VERSION 5.7 ;
  NOWIREEXTENSIONATPIN ON ;
  DIVIDERCHAR "/" ;
  BUSBITCHARS "[]" ;
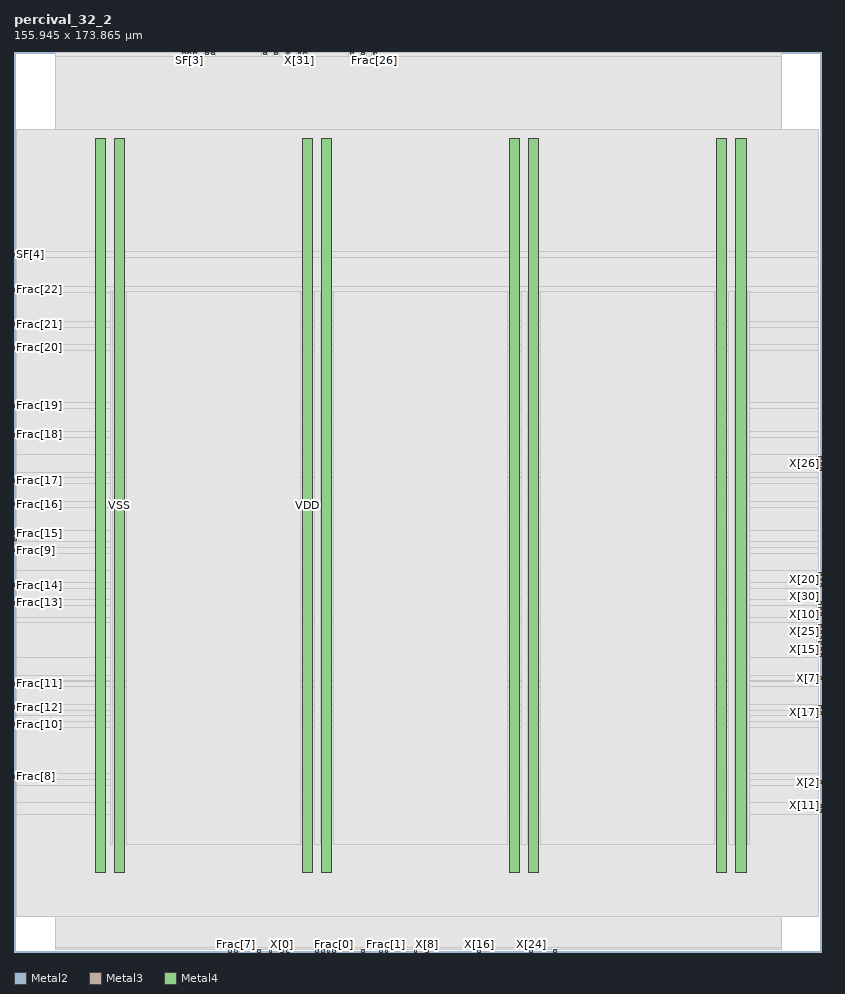
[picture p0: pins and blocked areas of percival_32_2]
MACRO percival_32_2
  CLASS BLOCK ;
  FOREIGN percival_32_2 ;
  ORIGIN 0.000 0.000 ;
  SIZE 155.945 BY 173.865 ;
  PIN Frac[0]
    DIRECTION OUTPUT ;
    USE SIGNAL ;
    ANTENNADIFFAREA 1.986000 ;
    PORT
      LAYER Metal2 ;
        RECT 61.600 0.000 62.160 0.560 ;
    END
  END Frac[0]
  PIN Frac[10]
    DIRECTION OUTPUT ;
    USE SIGNAL ;
    ANTENNADIFFAREA 1.986000 ;
    PORT
      LAYER Metal3 ;
        RECT 0.000 43.680 0.560 44.240 ;
    END
  END Frac[10]
  PIN Frac[11]
    DIRECTION OUTPUT ;
    USE SIGNAL ;
    ANTENNADIFFAREA 1.986000 ;
    PORT
      LAYER Metal3 ;
        RECT 0.000 51.520 0.560 52.080 ;
    END
  END Frac[11]
  PIN Frac[12]
    DIRECTION OUTPUT ;
    USE SIGNAL ;
    ANTENNADIFFAREA 1.986000 ;
    PORT
      LAYER Metal3 ;
        RECT 0.000 47.040 0.560 47.600 ;
    END
  END Frac[12]
  PIN Frac[13]
    DIRECTION OUTPUT ;
    USE SIGNAL ;
    ANTENNADIFFAREA 1.986000 ;
    PORT
      LAYER Metal3 ;
        RECT 0.000 67.200 0.560 67.760 ;
    END
  END Frac[13]
  PIN Frac[14]
    DIRECTION OUTPUT ;
    USE SIGNAL ;
    ANTENNADIFFAREA 1.986000 ;
    PORT
      LAYER Metal3 ;
        RECT 0.000 70.560 0.560 71.120 ;
    END
  END Frac[14]
  PIN Frac[15]
    DIRECTION OUTPUT ;
    USE SIGNAL ;
    ANTENNADIFFAREA 1.986000 ;
    PORT
      LAYER Metal3 ;
        RECT 0.000 80.640 0.560 81.200 ;
    END
  END Frac[15]
  PIN Frac[16]
    DIRECTION OUTPUT ;
    USE SIGNAL ;
    ANTENNADIFFAREA 1.986000 ;
    PORT
      LAYER Metal3 ;
        RECT 0.000 86.240 0.560 86.800 ;
    END
  END Frac[16]
  PIN Frac[17]
    DIRECTION OUTPUT ;
    USE SIGNAL ;
    ANTENNADIFFAREA 1.986000 ;
    PORT
      LAYER Metal3 ;
        RECT 0.000 90.720 0.560 91.280 ;
    END
  END Frac[17]
  PIN Frac[18]
    DIRECTION OUTPUT ;
    USE SIGNAL ;
    ANTENNADIFFAREA 1.986000 ;
    PORT
      LAYER Metal3 ;
        RECT 0.000 99.680 0.560 100.240 ;
    END
  END Frac[18]
  PIN Frac[19]
    DIRECTION OUTPUT ;
    USE SIGNAL ;
    ANTENNADIFFAREA 1.986000 ;
    PORT
      LAYER Metal3 ;
        RECT 0.000 105.280 0.560 105.840 ;
    END
  END Frac[19]
  PIN Frac[1]
    DIRECTION OUTPUT ;
    USE SIGNAL ;
    ANTENNADIFFAREA 1.986000 ;
    PORT
      LAYER Metal2 ;
        RECT 71.680 0.000 72.240 0.560 ;
    END
  END Frac[1]
  PIN Frac[20]
    DIRECTION OUTPUT ;
    USE SIGNAL ;
    ANTENNADIFFAREA 1.986000 ;
    PORT
      LAYER Metal3 ;
        RECT 0.000 116.480 0.560 117.040 ;
    END
  END Frac[20]
  PIN Frac[21]
    DIRECTION OUTPUT ;
    USE SIGNAL ;
    ANTENNADIFFAREA 1.986000 ;
    PORT
      LAYER Metal3 ;
        RECT 0.000 120.960 0.560 121.520 ;
    END
  END Frac[21]
  PIN Frac[22]
    DIRECTION OUTPUT ;
    USE SIGNAL ;
    ANTENNADIFFAREA 1.986000 ;
    PORT
      LAYER Metal3 ;
        RECT 0.000 127.680 0.560 128.240 ;
    END
  END Frac[22]
  PIN Frac[23]
    DIRECTION OUTPUT ;
    USE SIGNAL ;
    ANTENNADIFFAREA 1.986000 ;
    PORT
      LAYER Metal2 ;
        RECT 48.160 173.305 48.720 173.865 ;
    END
  END Frac[23]
  PIN Frac[24]
    DIRECTION OUTPUT ;
    USE SIGNAL ;
    ANTENNADIFFAREA 1.986000 ;
    PORT
      LAYER Metal2 ;
        RECT 50.400 173.305 50.960 173.865 ;
    END
  END Frac[24]
  PIN Frac[25]
    DIRECTION OUTPUT ;
    USE SIGNAL ;
    ANTENNADIFFAREA 1.986000 ;
    PORT
      LAYER Metal2 ;
        RECT 52.640 173.305 53.200 173.865 ;
    END
  END Frac[25]
  PIN Frac[26]
    DIRECTION OUTPUT ;
    USE SIGNAL ;
    ANTENNADIFFAREA 1.986000 ;
    PORT
      LAYER Metal2 ;
        RECT 69.440 173.305 70.000 173.865 ;
    END
  END Frac[26]
  PIN Frac[2]
    DIRECTION OUTPUT ;
    USE SIGNAL ;
    ANTENNADIFFAREA 1.986000 ;
    PORT
      LAYER Metal3 ;
        RECT 0.000 79.520 0.560 80.080 ;
    END
  END Frac[2]
  PIN Frac[3]
    DIRECTION OUTPUT ;
    USE SIGNAL ;
    ANTENNADIFFAREA 1.986000 ;
    PORT
      LAYER Metal2 ;
        RECT 77.280 0.000 77.840 0.560 ;
    END
  END Frac[3]
  PIN Frac[4]
    DIRECTION OUTPUT ;
    USE SIGNAL ;
    ANTENNADIFFAREA 1.986000 ;
    PORT
      LAYER Metal2 ;
        RECT 59.360 0.000 59.920 0.560 ;
    END
  END Frac[4]
  PIN Frac[5]
    DIRECTION OUTPUT ;
    USE SIGNAL ;
    ANTENNADIFFAREA 1.986000 ;
    PORT
      LAYER Metal2 ;
        RECT 47.040 0.000 47.600 0.560 ;
    END
  END Frac[5]
  PIN Frac[6]
    DIRECTION OUTPUT ;
    USE SIGNAL ;
    ANTENNADIFFAREA 1.986000 ;
    PORT
      LAYER Metal2 ;
        RECT 41.440 0.000 42.000 0.560 ;
    END
  END Frac[6]
  PIN Frac[7]
    DIRECTION OUTPUT ;
    USE SIGNAL ;
    ANTENNADIFFAREA 1.986000 ;
    PORT
      LAYER Metal2 ;
        RECT 42.560 0.000 43.120 0.560 ;
    END
  END Frac[7]
  PIN Frac[8]
    DIRECTION OUTPUT ;
    USE SIGNAL ;
    ANTENNADIFFAREA 1.986000 ;
    PORT
      LAYER Metal3 ;
        RECT 0.000 33.600 0.560 34.160 ;
    END
  END Frac[8]
  PIN Frac[9]
    DIRECTION OUTPUT ;
    USE SIGNAL ;
    ANTENNADIFFAREA 2.365600 ;
    PORT
      LAYER Metal3 ;
        RECT 0.000 77.280 0.560 77.840 ;
    END
  END Frac[9]
  PIN NZN
    DIRECTION OUTPUT ;
    USE SIGNAL ;
    ANTENNADIFFAREA 1.986000 ;
    PORT
      LAYER Metal2 ;
        RECT 104.160 0.000 104.720 0.560 ;
    END
  END NZN
  PIN SF[0]
    DIRECTION OUTPUT ;
    USE SIGNAL ;
    ANTENNADIFFAREA 1.986000 ;
    PORT
      LAYER Metal2 ;
        RECT 64.960 173.305 65.520 173.865 ;
    END
  END SF[0]
  PIN SF[1]
    DIRECTION OUTPUT ;
    USE SIGNAL ;
    ANTENNADIFFAREA 1.986000 ;
    PORT
      LAYER Metal2 ;
        RECT 67.200 173.305 67.760 173.865 ;
    END
  END SF[1]
  PIN SF[2]
    DIRECTION OUTPUT ;
    USE SIGNAL ;
    ANTENNADIFFAREA 1.986000 ;
    PORT
      LAYER Metal2 ;
        RECT 32.480 173.305 33.040 173.865 ;
    END
  END SF[2]
  PIN SF[3]
    DIRECTION OUTPUT ;
    USE SIGNAL ;
    ANTENNADIFFAREA 1.986000 ;
    PORT
      LAYER Metal2 ;
        RECT 33.600 173.305 34.160 173.865 ;
    END
  END SF[3]
  PIN SF[4]
    DIRECTION OUTPUT ;
    USE SIGNAL ;
    ANTENNADIFFAREA 1.986000 ;
    PORT
      LAYER Metal3 ;
        RECT 0.000 134.400 0.560 134.960 ;
    END
  END SF[4]
  PIN SF[5]
    DIRECTION OUTPUT ;
    USE SIGNAL ;
    ANTENNADIFFAREA 1.986000 ;
    PORT
      LAYER Metal2 ;
        RECT 38.080 173.305 38.640 173.865 ;
    END
  END SF[5]
  PIN SF[6]
    DIRECTION OUTPUT ;
    USE SIGNAL ;
    ANTENNADIFFAREA 1.986000 ;
    PORT
      LAYER Metal2 ;
        RECT 34.720 173.305 35.280 173.865 ;
    END
  END SF[6]
  PIN SF[7]
    DIRECTION OUTPUT ;
    USE SIGNAL ;
    ANTENNADIFFAREA 1.986000 ;
    PORT
      LAYER Metal2 ;
        RECT 36.960 173.305 37.520 173.865 ;
    END
  END SF[7]
  PIN Sign
    DIRECTION OUTPUT ;
    USE SIGNAL ;
    ANTENNADIFFAREA 1.986000 ;
    PORT
      LAYER Metal2 ;
        RECT 56.000 173.305 56.560 173.865 ;
    END
  END Sign
  PIN VDD
    DIRECTION INOUT ;
    USE POWER ;
    PORT
      LAYER Metal4 ;
        RECT 15.720 15.380 17.720 157.100 ;
    END
    PORT
      LAYER Metal4 ;
        RECT 55.720 15.380 57.720 157.100 ;
    END
    PORT
      LAYER Metal4 ;
        RECT 95.720 15.380 97.720 157.100 ;
    END
    PORT
      LAYER Metal4 ;
        RECT 135.720 15.380 137.720 157.100 ;
    END
  END VDD
  PIN VSS
    DIRECTION INOUT ;
    USE GROUND ;
    PORT
      LAYER Metal4 ;
        RECT 19.420 15.380 21.420 157.100 ;
    END
    PORT
      LAYER Metal4 ;
        RECT 59.420 15.380 61.420 157.100 ;
    END
    PORT
      LAYER Metal4 ;
        RECT 99.420 15.380 101.420 157.100 ;
    END
    PORT
      LAYER Metal4 ;
        RECT 139.420 15.380 141.420 157.100 ;
    END
  END VSS
  PIN X[0]
    DIRECTION INPUT ;
    USE SIGNAL ;
    ANTENNAGATEAREA 0.498500 ;
    PORT
      LAYER Metal2 ;
        RECT 51.520 0.000 52.080 0.560 ;
    END
  END X[0]
  PIN X[10]
    DIRECTION INPUT ;
    USE SIGNAL ;
    ANTENNAGATEAREA 0.498500 ;
    PORT
      LAYER Metal3 ;
        RECT 155.385 64.960 155.945 65.520 ;
    END
  END X[10]
  PIN X[11]
    DIRECTION INPUT ;
    USE SIGNAL ;
    ANTENNAGATEAREA 0.498500 ;
    PORT
      LAYER Metal3 ;
        RECT 155.385 28.000 155.945 28.560 ;
    END
  END X[11]
  PIN X[12]
    DIRECTION INPUT ;
    USE SIGNAL ;
    ANTENNAGATEAREA 0.498500 ;
    PORT
      LAYER Metal3 ;
        RECT 155.385 62.720 155.945 63.280 ;
    END
  END X[12]
  PIN X[13]
    DIRECTION INPUT ;
    USE SIGNAL ;
    ANTENNAGATEAREA 0.726000 ;
    PORT
      LAYER Metal3 ;
        RECT 155.385 66.080 155.945 66.640 ;
    END
  END X[13]
  PIN X[14]
    DIRECTION INPUT ;
    USE SIGNAL ;
    ANTENNAGATEAREA 0.726000 ;
    PORT
      LAYER Metal3 ;
        RECT 155.385 57.120 155.945 57.680 ;
    END
  END X[14]
  PIN X[15]
    DIRECTION INPUT ;
    USE SIGNAL ;
    ANTENNAGATEAREA 0.726000 ;
    PORT
      LAYER Metal3 ;
        RECT 155.385 58.240 155.945 58.800 ;
    END
  END X[15]
  PIN X[16]
    DIRECTION INPUT ;
    USE SIGNAL ;
    ANTENNAGATEAREA 1.102000 ;
    PORT
      LAYER Metal2 ;
        RECT 89.600 0.000 90.160 0.560 ;
    END
  END X[16]
  PIN X[17]
    DIRECTION INPUT ;
    USE SIGNAL ;
    ANTENNAGATEAREA 1.102000 ;
    PORT
      LAYER Metal3 ;
        RECT 155.385 45.920 155.945 46.480 ;
    END
  END X[17]
  PIN X[18]
    DIRECTION INPUT ;
    USE SIGNAL ;
    ANTENNAGATEAREA 0.498500 ;
    PORT
      LAYER Metal3 ;
        RECT 155.385 72.800 155.945 73.360 ;
    END
  END X[18]
  PIN X[19]
    DIRECTION INPUT ;
    USE SIGNAL ;
    ANTENNAGATEAREA 0.726000 ;
    PORT
      LAYER Metal3 ;
        RECT 155.385 47.040 155.945 47.600 ;
    END
  END X[19]
  PIN X[1]
    DIRECTION INPUT ;
    USE SIGNAL ;
    ANTENNAGATEAREA 0.498500 ;
    PORT
      LAYER Metal2 ;
        RECT 49.280 0.000 49.840 0.560 ;
    END
  END X[1]
  PIN X[20]
    DIRECTION INPUT ;
    USE SIGNAL ;
    ANTENNAGATEAREA 0.498500 ;
    PORT
      LAYER Metal3 ;
        RECT 155.385 71.680 155.945 72.240 ;
    END
  END X[20]
  PIN X[21]
    DIRECTION INPUT ;
    USE SIGNAL ;
    ANTENNAGATEAREA 0.498500 ;
    PORT
      LAYER Metal3 ;
        RECT 155.385 70.560 155.945 71.120 ;
    END
  END X[21]
  PIN X[22]
    DIRECTION INPUT ;
    USE SIGNAL ;
    ANTENNAGATEAREA 0.498500 ;
    PORT
      LAYER Metal3 ;
        RECT 155.385 59.360 155.945 59.920 ;
    END
  END X[22]
  PIN X[23]
    DIRECTION INPUT ;
    USE SIGNAL ;
    ANTENNAGATEAREA 0.726000 ;
    PORT
      LAYER Metal3 ;
        RECT 155.385 60.480 155.945 61.040 ;
    END
  END X[23]
  PIN X[24]
    DIRECTION INPUT ;
    USE SIGNAL ;
    ANTENNAGATEAREA 0.726000 ;
    PORT
      LAYER Metal2 ;
        RECT 99.680 0.000 100.240 0.560 ;
    END
  END X[24]
  PIN X[25]
    DIRECTION INPUT ;
    USE SIGNAL ;
    ANTENNAGATEAREA 0.726000 ;
    PORT
      LAYER Metal3 ;
        RECT 155.385 61.600 155.945 62.160 ;
    END
  END X[25]
  PIN X[26]
    DIRECTION INPUT ;
    USE SIGNAL ;
    ANTENNAGATEAREA 0.498500 ;
    PORT
      LAYER Metal3 ;
        RECT 155.385 94.080 155.945 94.640 ;
    END
  END X[26]
  PIN X[27]
    DIRECTION INPUT ;
    USE SIGNAL ;
    ANTENNAGATEAREA 1.102000 ;
    PORT
      LAYER Metal3 ;
        RECT 155.385 26.880 155.945 27.440 ;
    END
  END X[27]
  PIN X[28]
    DIRECTION INPUT ;
    USE SIGNAL ;
    ANTENNAGATEAREA 0.726000 ;
    PORT
      LAYER Metal3 ;
        RECT 155.385 92.960 155.945 93.520 ;
    END
  END X[28]
  PIN X[29]
    DIRECTION INPUT ;
    USE SIGNAL ;
    ANTENNAGATEAREA 1.102000 ;
    PORT
      LAYER Metal3 ;
        RECT 155.385 95.200 155.945 95.760 ;
    END
  END X[29]
  PIN X[2]
    DIRECTION INPUT ;
    USE SIGNAL ;
    ANTENNAGATEAREA 0.498500 ;
    PORT
      LAYER Metal3 ;
        RECT 155.385 32.480 155.945 33.040 ;
    END
  END X[2]
  PIN X[30]
    DIRECTION INPUT ;
    USE SIGNAL ;
    ANTENNAGATEAREA 1.102000 ;
    PORT
      LAYER Metal3 ;
        RECT 155.385 67.200 155.945 67.760 ;
    END
  END X[30]
  PIN X[31]
    DIRECTION INPUT ;
    USE SIGNAL ;
    ANTENNAGATEAREA 0.498500 ;
    PORT
      LAYER Metal2 ;
        RECT 54.880 173.305 55.440 173.865 ;
    END
  END X[31]
  PIN X[3]
    DIRECTION INPUT ;
    USE SIGNAL ;
    ANTENNAGATEAREA 0.498500 ;
    PORT
      LAYER Metal2 ;
        RECT 60.480 0.000 61.040 0.560 ;
    END
  END X[3]
  PIN X[4]
    DIRECTION INPUT ;
    USE SIGNAL ;
    ANTENNAGATEAREA 0.498500 ;
    PORT
      LAYER Metal2 ;
        RECT 58.240 0.000 58.800 0.560 ;
    END
  END X[4]
  PIN X[5]
    DIRECTION INPUT ;
    USE SIGNAL ;
    ANTENNAGATEAREA 0.498500 ;
    PORT
      LAYER Metal2 ;
        RECT 52.640 0.000 53.200 0.560 ;
    END
  END X[5]
  PIN X[6]
    DIRECTION INPUT ;
    USE SIGNAL ;
    ANTENNAGATEAREA 0.498500 ;
    PORT
      LAYER Metal2 ;
        RECT 70.560 0.000 71.120 0.560 ;
    END
  END X[6]
  PIN X[7]
    DIRECTION INPUT ;
    USE SIGNAL ;
    ANTENNAGATEAREA 0.726000 ;
    PORT
      LAYER Metal3 ;
        RECT 155.385 52.640 155.945 53.200 ;
    END
  END X[7]
  PIN X[8]
    DIRECTION INPUT ;
    USE SIGNAL ;
    ANTENNAGATEAREA 0.498500 ;
    PORT
      LAYER Metal2 ;
        RECT 79.520 0.000 80.080 0.560 ;
    END
  END X[8]
  PIN X[9]
    DIRECTION INPUT ;
    USE SIGNAL ;
    ANTENNAGATEAREA 0.498500 ;
    PORT
      LAYER Metal2 ;
        RECT 67.200 0.000 67.760 0.560 ;
    END
  END X[9]
  OBS
      LAYER Nwell ;
        RECT 6.290 15.250 149.390 157.230 ;
      LAYER Metal1 ;
        RECT 6.720 15.380 148.960 157.100 ;
      LAYER Metal2 ;
        RECT 7.980 173.005 32.180 173.725 ;
        RECT 35.580 173.005 36.660 173.725 ;
        RECT 38.940 173.005 47.860 173.725 ;
        RECT 49.020 173.005 50.100 173.725 ;
        RECT 51.260 173.005 52.340 173.725 ;
        RECT 53.500 173.005 54.580 173.725 ;
        RECT 56.860 173.005 64.660 173.725 ;
        RECT 65.820 173.005 66.900 173.725 ;
        RECT 68.060 173.005 69.140 173.725 ;
        RECT 70.300 173.005 148.260 173.725 ;
        RECT 7.980 0.860 148.260 173.005 ;
        RECT 7.980 0.560 41.140 0.860 ;
        RECT 43.420 0.560 46.740 0.860 ;
        RECT 47.900 0.560 48.980 0.860 ;
        RECT 50.140 0.560 51.220 0.860 ;
        RECT 53.500 0.560 57.940 0.860 ;
        RECT 62.460 0.560 66.900 0.860 ;
        RECT 68.060 0.560 70.260 0.860 ;
        RECT 72.540 0.560 76.980 0.860 ;
        RECT 78.140 0.560 79.220 0.860 ;
        RECT 80.380 0.560 89.300 0.860 ;
        RECT 90.460 0.560 99.380 0.860 ;
        RECT 100.540 0.560 103.860 0.860 ;
        RECT 105.020 0.560 148.260 0.860 ;
      LAYER Metal3 ;
        RECT 0.560 135.260 155.385 158.900 ;
        RECT 0.860 134.100 155.385 135.260 ;
        RECT 0.560 128.540 155.385 134.100 ;
        RECT 0.860 127.380 155.385 128.540 ;
        RECT 0.560 121.820 155.385 127.380 ;
        RECT 0.860 120.660 155.385 121.820 ;
        RECT 0.560 117.340 155.385 120.660 ;
        RECT 0.860 116.180 155.385 117.340 ;
        RECT 0.560 106.140 155.385 116.180 ;
        RECT 0.860 104.980 155.385 106.140 ;
        RECT 0.560 100.540 155.385 104.980 ;
        RECT 0.860 99.380 155.385 100.540 ;
        RECT 0.560 96.060 155.385 99.380 ;
        RECT 0.560 92.660 155.085 96.060 ;
        RECT 0.560 91.580 155.385 92.660 ;
        RECT 0.860 90.420 155.385 91.580 ;
        RECT 0.560 87.100 155.385 90.420 ;
        RECT 0.860 85.940 155.385 87.100 ;
        RECT 0.560 81.500 155.385 85.940 ;
        RECT 0.860 79.220 155.385 81.500 ;
        RECT 0.560 78.140 155.385 79.220 ;
        RECT 0.860 76.980 155.385 78.140 ;
        RECT 0.560 73.660 155.385 76.980 ;
        RECT 0.560 71.420 155.085 73.660 ;
        RECT 0.860 70.260 155.085 71.420 ;
        RECT 0.560 68.060 155.385 70.260 ;
        RECT 0.860 66.900 155.085 68.060 ;
        RECT 0.560 64.660 155.085 66.900 ;
        RECT 0.560 63.580 155.385 64.660 ;
        RECT 0.560 56.820 155.085 63.580 ;
        RECT 0.560 53.500 155.385 56.820 ;
        RECT 0.560 52.380 155.085 53.500 ;
        RECT 0.860 52.340 155.085 52.380 ;
        RECT 0.860 51.220 155.385 52.340 ;
        RECT 0.560 47.900 155.385 51.220 ;
        RECT 0.860 46.740 155.085 47.900 ;
        RECT 0.560 45.620 155.085 46.740 ;
        RECT 0.560 44.540 155.385 45.620 ;
        RECT 0.860 43.380 155.385 44.540 ;
        RECT 0.560 34.460 155.385 43.380 ;
        RECT 0.860 33.340 155.385 34.460 ;
        RECT 0.860 33.300 155.085 33.340 ;
        RECT 0.560 32.180 155.085 33.300 ;
        RECT 0.560 28.860 155.385 32.180 ;
        RECT 0.560 26.580 155.085 28.860 ;
        RECT 0.560 6.860 155.385 26.580 ;
      LAYER Metal4 ;
        RECT 18.620 20.810 19.120 127.590 ;
        RECT 21.720 20.810 55.420 127.590 ;
        RECT 58.020 20.810 59.120 127.590 ;
        RECT 61.720 20.810 95.420 127.590 ;
        RECT 98.020 20.810 99.120 127.590 ;
        RECT 101.720 20.810 135.420 127.590 ;
        RECT 138.020 20.810 139.120 127.590 ;
        RECT 141.720 20.810 142.100 127.590 ;
  END
END percival_32_2
END LIBRARY

